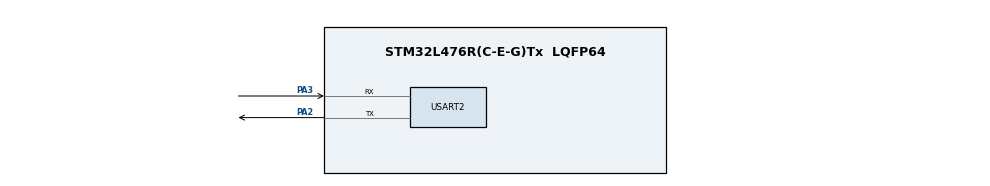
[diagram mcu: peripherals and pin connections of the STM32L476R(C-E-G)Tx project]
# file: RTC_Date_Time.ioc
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Mcu.Family=STM32L4
Mcu.Name=STM32L476R(C-E-G)Tx
Mcu.Package=LQFP64
NVIC.PriorityGroup=NVIC_PRIORITYGROUP_4
PA2.Mode=Asynchronous
PA2.Signal=USART2_TX
PA3.Mode=Asynchronous
PA3.Signal=USART2_RX
PC14-OSC32_IN\ (PC14).Mode=LSE-External-Oscillator
PC14-OSC32_IN\ (PC14).Signal=RCC_OSC32_IN
PC15-OSC32_OUT\ (PC15).Mode=LSE-External-Oscillator
PC15-OSC32_OUT\ (PC15).Signal=RCC_OSC32_OUT
PH0-OSC_IN\ (PH0).Mode=HSE-External-Oscillator
PH0-OSC_IN\ (PH0).Signal=RCC_OSC_IN
PH1-OSC_OUT\ (PH1).Mode=HSE-External-Oscillator
PH1-OSC_OUT\ (PH1).Signal=RCC_OSC_OUT
ProjectManager.HeapSize=0x200
ProjectManager.StackSize=0x400
ProjectManager.TargetToolchain=Makefile
RCC.HSE_VALUE=8000000
RCC.HSI_VALUE=16000000
RCC.MSI_VALUE=4000000
RCC.VCOOutputFreq_Value=32000000
USART2.VirtualMode-Asynchronous=VM_ASYNC
VP_RTC_VS_RTC_Activate.Mode=RTC_Enabled
VP_RTC_VS_RTC_Calendar.Mode=RTC_Calendar
board=custom

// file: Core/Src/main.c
/* USER CODE BEGIN Header */
/**
  ******************************************************************************
  * @file           : main.c
  * @brief          : Main program body
  ******************************************************************************
  * @attention
  *
  * Copyright (c) 2023 STMicroelectronics.
  * All rights reserved.
  *
  * This software is licensed under terms that can be found in the LICENSE file
  * in the root directory of this software component.
  * If no LICENSE file comes with this software, it is provided AS-IS.
  *
  ******************************************************************************
  */
/* USER CODE END Header */
#include "main.h"

RTC_HandleTypeDef hrtc;

UART_HandleTypeDef huart2;

void SystemClock_Config(void);
static void MX_GPIO_Init(void);
static void MX_USART2_UART_Init(void);
static void MX_RTC_Init(void);

int main(void)
{

  /* MCU Configuration--------------------------------------------------------*/

  /* Reset of all peripherals, Initializes the Flash interface and the Systick. */
  HAL_Init();

  /* Configure the system clock */
  SystemClock_Config();

  /* Initialize all configured peripherals */
  MX_GPIO_Init();
  MX_USART2_UART_Init();
  MX_RTC_Init();

  /* Infinite loop */
  while (1)
  {

  }
}

void SystemClock_Config(void)
{
  RCC_OscInitTypeDef RCC_OscInitStruct = {0};
  RCC_ClkInitTypeDef RCC_ClkInitStruct = {0};

  /** Configure the main internal regulator output voltage
  */
  __HAL_RCC_PWR_CLK_ENABLE();
  __HAL_PWR_VOLTAGESCALING_CONFIG(PWR_REGULATOR_VOLTAGE_SCALE1);
  /** Initializes the RCC Oscillators according to the specified parameters
  * in the RCC_OscInitTypeDef structure.
  */
  RCC_OscInitStruct.OscillatorType = RCC_OSCILLATORTYPE_HSI|RCC_OSCILLATORTYPE_LSI;
  RCC_OscInitStruct.LSEState = RCC_LSE_ON;
  RCC_OscInitStruct.HSIState = RCC_HSI_ON;
  RCC_OscInitStruct.HSICalibrationValue = RCC_HSICALIBRATION_DEFAULT;
  RCC_OscInitStruct.LSIState = RCC_LSI_ON;
  RCC_OscInitStruct.PLL.PLLState = RCC_PLL_ON;
  RCC_OscInitStruct.PLL.PLLSource = RCC_PLLSOURCE_HSI;
  RCC_OscInitStruct.PLL.PLLM = 1;             // L4 ma inny prescaler M (1-8)
  RCC_OscInitStruct.PLL.PLLN = 10;            // N (mnożnik)
  RCC_OscInitStruct.PLL.PLLP = RCC_PLLP_DIV7; // P (SAI audio), nieużywane dla SYSCLK
  RCC_OscInitStruct.PLL.PLLQ = RCC_PLLQ_DIV2; // Q (USB/RNG), DIV2, DIV4, DIV6, DIV8
  RCC_OscInitStruct.PLL.PLLR = RCC_PLLR_DIV2; // R (SYSCLK), to jest główne wyjście!

  if (HAL_RCC_OscConfig(&RCC_OscInitStruct) != HAL_OK)
  {
    Error_Handler();
  }
  /** Initializes the CPU, AHB and APB buses clocks
  */
  RCC_ClkInitStruct.ClockType = RCC_CLOCKTYPE_HCLK|RCC_CLOCKTYPE_SYSCLK
                              |RCC_CLOCKTYPE_PCLK1|RCC_CLOCKTYPE_PCLK2;
  RCC_ClkInitStruct.SYSCLKSource = RCC_SYSCLKSOURCE_PLLCLK;
  RCC_ClkInitStruct.AHBCLKDivider = RCC_SYSCLK_DIV1;
  RCC_ClkInitStruct.APB1CLKDivider = RCC_HCLK_DIV2;
  RCC_ClkInitStruct.APB2CLKDivider = RCC_HCLK_DIV1;

  if (HAL_RCC_ClockConfig(&RCC_ClkInitStruct, FLASH_LATENCY_2) != HAL_OK)
  {
    Error_Handler();
  }
}

static void MX_RTC_Init(void)
{

  /** Initialize RTC Only
  */
  hrtc.Instance = RTC;
  hrtc.Init.HourFormat = RTC_HOURFORMAT_24;
  hrtc.Init.AsynchPrediv = 127;
  hrtc.Init.SynchPrediv = 255;
  hrtc.Init.OutPut = RTC_OUTPUT_DISABLE;
  hrtc.Init.OutPutPolarity = RTC_OUTPUT_POLARITY_HIGH;
  hrtc.Init.OutPutType = RTC_OUTPUT_TYPE_OPENDRAIN;
  if (HAL_RTC_Init(&hrtc) != HAL_OK)
  {
    Error_Handler();
  }

}

static void MX_USART2_UART_Init(void)
{

  huart2.Instance = USART2;
  huart2.Init.BaudRate = 115200;
  huart2.Init.WordLength = UART_WORDLENGTH_8B;
  huart2.Init.StopBits = UART_STOPBITS_1;
  huart2.Init.Parity = UART_PARITY_NONE;
  huart2.Init.Mode = UART_MODE_TX_RX;
  huart2.Init.HwFlowCtl = UART_HWCONTROL_NONE;
  huart2.Init.OverSampling = UART_OVERSAMPLING_16;
  if (HAL_UART_Init(&huart2) != HAL_OK)
  {
    Error_Handler();
  }

}

static void MX_GPIO_Init(void)
{
  GPIO_InitTypeDef GPIO_InitStruct = {0};

  /* GPIO Ports Clock Enable */
  __HAL_RCC_GPIOC_CLK_ENABLE();
  __HAL_RCC_GPIOH_CLK_ENABLE();
  __HAL_RCC_GPIOA_CLK_ENABLE();
  __HAL_RCC_GPIOB_CLK_ENABLE();

  /*Configure GPIO pin Output Level */
  HAL_GPIO_WritePin(LD2_GPIO_Port, LD2_Pin, GPIO_PIN_RESET);

  /*Configure GPIO pin : B1_Pin */
  GPIO_InitStruct.Pin = B1_Pin;
  GPIO_InitStruct.Mode = GPIO_MODE_IT_FALLING;
  GPIO_InitStruct.Pull = GPIO_NOPULL;
  HAL_GPIO_Init(B1_GPIO_Port, &GPIO_InitStruct);

  /*Configure GPIO pin : LD2_Pin */
  GPIO_InitStruct.Pin = LD2_Pin;
  GPIO_InitStruct.Mode = GPIO_MODE_OUTPUT_PP;
  GPIO_InitStruct.Pull = GPIO_NOPULL;
  GPIO_InitStruct.Speed = GPIO_SPEED_FREQ_LOW;
  HAL_GPIO_Init(LD2_GPIO_Port, &GPIO_InitStruct);

}

void Error_Handler(void)
{
  __disable_irq();
  while (1)
  {
  }
}
